One B-rep face of a CAD part: STEP entity #490.
In plain terms, the planar face has unit normal (1, 0, 0).
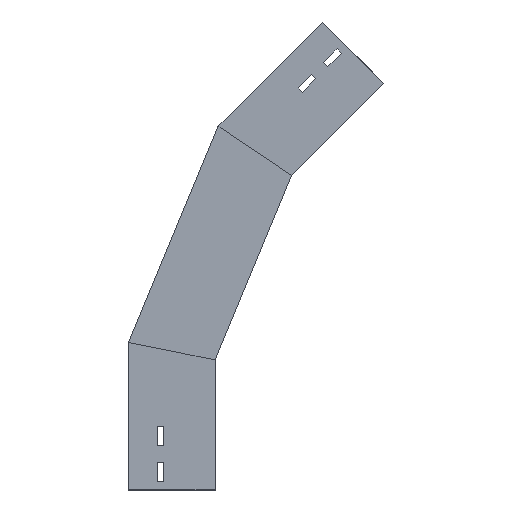
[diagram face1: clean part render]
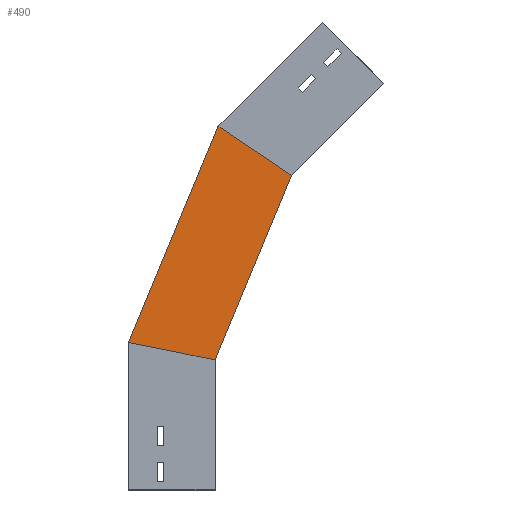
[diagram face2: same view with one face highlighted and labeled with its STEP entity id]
Its self-contained STEP definition (entity closure, numbers rounded to 3 decimals):
#53 = FACE_OUTER_BOUND ( 'NONE', #355, .T. ) ;
#57 = LINE ( 'NONE', #259, #348 ) ;
#59 = CARTESIAN_POINT ( 'NONE',  ( 0., 100., 169.891 ) ) ;
#71 = DIRECTION ( 'NONE',  ( 0., -0.981, -0.195 ) ) ;
#143 = LINE ( 'NONE', #960, #975 ) ;
#145 = VERTEX_POINT ( 'NONE', #59 ) ;
#169 = AXIS2_PLACEMENT_3D ( 'NONE', #619, #871, #507 ) ;
#250 = EDGE_CURVE ( 'NONE', #145, #1211, #1282, .T. ) ;
#259 = CARTESIAN_POINT ( 'NONE',  ( 0., 8.412, 129.693 ) ) ;
#260 = ORIENTED_EDGE ( 'NONE', *, *, #250, .T. ) ;
#306 = ORIENTED_EDGE ( 'NONE', *, *, #793, .F. ) ;
#328 = LINE ( 'NONE', #1449, #1436 ) ;
#348 = VECTOR ( 'NONE', #1326, 1000. ) ;
#355 = EDGE_LOOP ( 'NONE', ( #260, #1315, #1148, #306 ) ) ;
#381 = DIRECTION ( 'NONE',  ( 0., -0.831, -0.556 ) ) ;
#427 = EDGE_CURVE ( 'NONE', #1211, #1429, #143, .T. ) ;
#444 = VECTOR ( 'NONE', #1020, 1000. ) ;
#490 = ADVANCED_FACE ( 'NONE', ( #53 ), #521, .T. ) ;
#501 = CARTESIAN_POINT ( 'NONE',  ( 0., -3.241, 419.138 ) ) ;
#507 = DIRECTION ( 'NONE',  ( 0., 0., -1. ) ) ;
#521 = PLANE ( 'NONE',  #169 ) ;
#532 = CARTESIAN_POINT ( 'NONE',  ( 0., -88.017, 362.492 ) ) ;
#619 = CARTESIAN_POINT ( 'NONE',  ( 0., 8.412, 129.693 ) ) ;
#691 = CARTESIAN_POINT ( 'NONE',  ( 0., 100.799, 167.961 ) ) ;
#780 = VERTEX_POINT ( 'NONE', #1489 ) ;
#793 = EDGE_CURVE ( 'NONE', #145, #780, #328, .T. ) ;
#871 = DIRECTION ( 'NONE',  ( 1., 0., 0. ) ) ;
#960 = CARTESIAN_POINT ( 'NONE',  ( 0., -128.891, 335.181 ) ) ;
#975 = VECTOR ( 'NONE', #381, 1000. ) ;
#1020 = DIRECTION ( 'NONE',  ( 0., -0.383, 0.924 ) ) ;
#1148 = ORIENTED_EDGE ( 'NONE', *, *, #1301, .F. ) ;
#1211 = VERTEX_POINT ( 'NONE', #501 ) ;
#1282 = LINE ( 'NONE', #691, #444 ) ;
#1301 = EDGE_CURVE ( 'NONE', #780, #1429, #57, .T. ) ;
#1315 = ORIENTED_EDGE ( 'NONE', *, *, #427, .T. ) ;
#1326 = DIRECTION ( 'NONE',  ( 0., -0.383, 0.924 ) ) ;
#1429 = VERTEX_POINT ( 'NONE', #532 ) ;
#1436 = VECTOR ( 'NONE', #71, 1000. ) ;
#1449 = CARTESIAN_POINT ( 'NONE',  ( 0., -28.701, 144.291 ) ) ;
#1489 = CARTESIAN_POINT ( 'NONE',  ( 0., 0., 150. ) ) ;
